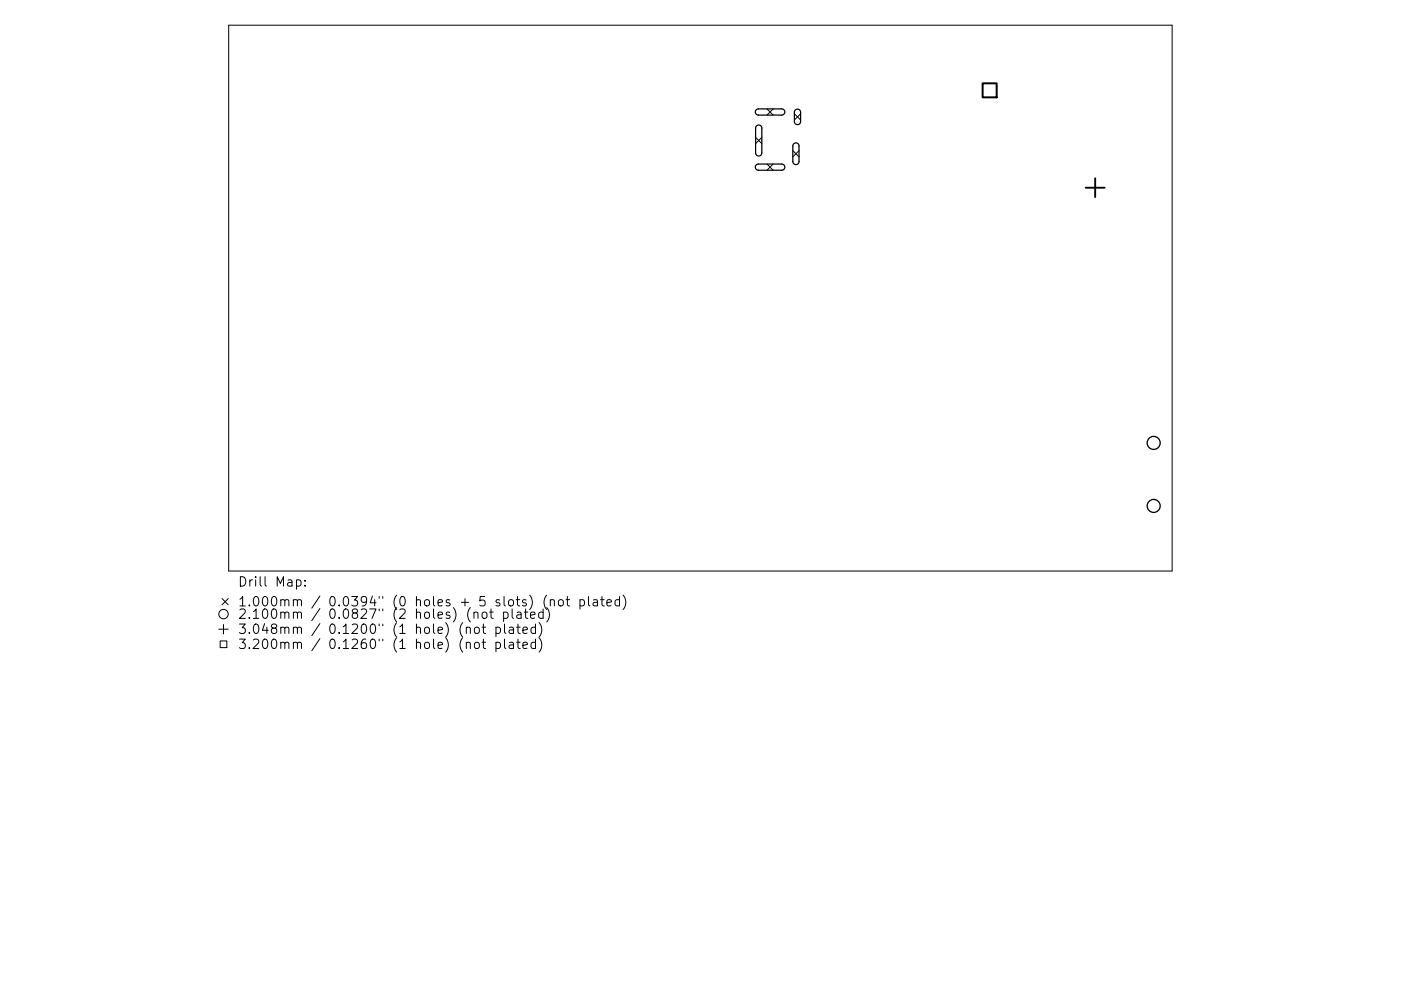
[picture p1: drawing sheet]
<svg xmlns="http://www.w3.org/2000/svg" width="297mm" height="210mm" viewBox="0 0 297 210" stroke-linecap="round" stroke-linejoin="round" font-family="sans-serif">
<defs><g id="words">
<g font-size="2.8">
<text x="50.4" y="125.1">Drill</text>
<text x="58.4" y="125.1">Map:</text>
<text x="50.4" y="129.3">1.000mm</text>
<text x="50.4" y="131.9">2.100mm</text>
<text x="69.8" y="129.3">0.0394&quot;</text>
<text x="69.8" y="131.9">0.0827&quot;</text>
<text x="83.6" y="129.3">(0</text>
<text x="83.6" y="131.9">(2</text>
<text x="88.5" y="129.3">holes</text>
<text x="88.5" y="131.9">holes)</text>
<text x="98.2" y="129.3">+</text>
<text x="99.6" y="131.9">(not</text>
<text x="102.4" y="129.3">5</text>
<text x="106.1" y="129.3">slots)</text>
<text x="107.4" y="131.9">plated)</text>
<text x="116.4" y="129.3">(not</text>
<text x="124.2" y="129.3">plated)</text>
<text x="50.4" y="135.1">3.048mm</text>
<text x="69.8" y="135.1">0.1200&quot;</text>
<text x="83.6" y="135.1">(1</text>
<text x="88.5" y="135.1">hole)</text>
<text x="98" y="135.1">(not</text>
<text x="105.8" y="135.1">plated)</text>
<text x="50.4" y="138.3">3.200mm</text>
<text x="69.8" y="138.3">0.1260&quot;</text>
<text x="83.6" y="138.3">(1</text>
<text x="88.5" y="138.3">hole)</text>
<text x="98" y="138.3">(not</text>
<text x="105.8" y="138.3">plated)</text>
</g>
</g></defs>
<g fill="none" stroke="#000" stroke-width=".21">
<path d="M48.5 5.3h200v115.9h-200zM160.2 29.2l1.3 1.3M161.5 29.2l-1.3 1.3M162.6 23.1l1.3 1.3M162.6 34.8l1.3 1.3M163.9 23.1l-1.3 1.3M163.9 34.8l-1.3 1.3M168.1 32l1.3 1.3M168.4 24.1l1.3 1.4M169.4 32l-1.3 1.3M169.7 24.1l-1.3 1.4M46.4 133.5h2"/>
<path d="M46.7 136h1.4v1.4h-1.4zM47.1 127l1.3 1.3M47.4 132.5v2M48.4 127l-1.3 1.3M56.2 122.4v1.7l.3 .3M62.2 127.4l.3-.2 .5 .1 .1 1.3M62.2 130.1a.5 .5 0 0 1 .9 0v1.1M62.2 133.3a.5 .5 0 0 1 .9 0v1.1M62.2 136.5a.5 .5 0 0 1 .9 0v1.1M63.1 127.5l.2-.3 .5 .1 .1 1.3M63.1 130.1l.2-.2 .5 .1 .1 1.2M63.1 133.3l.2-.2 .5 .1 .1 1.2"/>
<path d="M63.1 136.5l.2-.2 .5 .1 .1 1.2M67.8 126.5l-1.7 2.5M67.8 129.1l-1.7 2.6M67.8 132.3l-1.7 2.6M67.8 135.5l-1.7 2.6M80.4 126.6v.3M80.4 129.2v.4M80.4 132.4v.4M80.4 135.6v.4M81.2 126.6v.3M81.2 129.2v.4M81.2 132.4v.4"/>
<path d="M81.2 135.6v.4M105.9 127.3l-.5-.1-.2 .3v.3l.7 .2v.5h-.7M115.9 126.3a2.29 2.29 0 0 0 0 3M123 127.3l.5-.1 .4 .4v.6l-.2 .3h-.7M123 127.2v2"/>
<circle cx="47.4" cy="130.3" r="1"/>
</g>
<path d="M160.3 23.3l.5-.2h5l.4 .2 .2 .5-.2 .4-.4 .2h-5.1l-.5-.4zM160.3 35l.5-.2h5l.4 .2 .2 .5-.2 .4-.4 .2h-5.1l-.5-.4zM160.4 26.7l.7-.1 .4 .5v5.4l-.2 .4-.4 .2-.5-.2-.2-.4v-5.3zM168.3 30.5l.7-.1 .4 .5v3.5l-.2 .3-.4 .2-.5-.1-.2-.5v-3.4zM168.6 23.3l.7-.1 .4 .5v2.2l-.1 .4-.4 .1-.5-.1-.3-.4v-2.1z" fill="none" stroke="#000" stroke-width=".26"/>
<g fill="none" stroke="#000" stroke-width=".28">
<circle cx="244.6" cy="94" r="1.38"/>
<circle cx="244.6" cy="107.3" r="1.38"/>
</g>
<path d="M230.2 39.8h4M232.2 37.8v4" fill="none" stroke="#000" stroke-width=".4"/>
<path d="M208.3 17.7h3v3h-3z" fill="none" stroke="#000" stroke-width=".42"/>
<use href="#words"/>
</svg>
